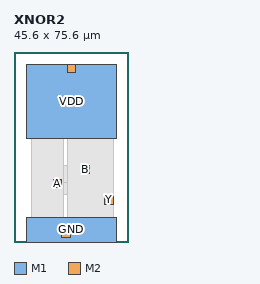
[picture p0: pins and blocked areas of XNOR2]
MACRO XNOR2
  CLASS CORE ;
  ORIGIN 0 0 ;
  SIZE 45.600 BY 75.600 ;
  SYMMETRY X Y ;
  SITE TR1um_access_site ;
  PIN VDD
    DIRECTION INOUT ;
    USE POWER ;
    PORT
      LAYER M1 ;
        RECT 5.000 41.000 40.600 70.800 ;
      LAYER M2 ;
        RECT 21.100 67.400 24.500 70.800 ;
    END
  END VDD
  PIN GND
    DIRECTION INOUT ;
    USE GROUND ;
    PORT
      LAYER M1 ;
        RECT 5.000 0.000 40.600 9.800 ;
      LAYER M2 ;
        RECT 18.900 1.600 22.300 5.000 ;
    END
  END GND
  PIN A
    DIRECTION INPUT ;
    USE SIGNAL ;
    PORT
      LAYER M2 ;
        RECT 15.600 21.600 19.000 25.000 ;
    END
  END A
  PIN B
    DIRECTION INPUT ;
    USE SIGNAL ;
    PORT
      LAYER M2 ;
        RECT 26.600 27.100 30.000 30.500 ;
    END
  END B
  PIN Y
    DIRECTION OUTPUT ;
    USE SIGNAL ;
    PORT
      LAYER M2 ;
        RECT 36.200 15.100 39.600 18.500 ;
    END
  END Y
  OBS
    LAYER M1 ;
      RECT 13.100 6.400 15.700 9.800 ;
    LAYER M1 ;
      RECT 25.100 6.400 35.700 13.600 ;
    LAYER M1 ;
      RECT 10.300 19.000 32.900 25.000 ;
    LAYER M1 ;
      RECT 15.900 23.800 30.000 30.500 ;
    LAYER M1 ;
      RECT 7.000 6.400 19.700 51.200 ;
    LAYER M1 ;
      RECT 29.100 41.000 31.700 51.200 ;
    LAYER M1 ;
      RECT 21.100 6.400 39.600 51.200 ;
    LAYER V1 ;
      RECT 19.900 2.600 21.300 4.000 ;
    LAYER V1 ;
      RECT 37.200 16.100 38.600 17.500 ;
    LAYER V1 ;
      RECT 16.600 22.600 18.000 24.000 ;
    LAYER V1 ;
      RECT 27.600 28.100 29.000 29.500 ;
    LAYER V1 ;
      RECT 22.100 68.400 23.500 69.800 ;
  END
END XNOR2
